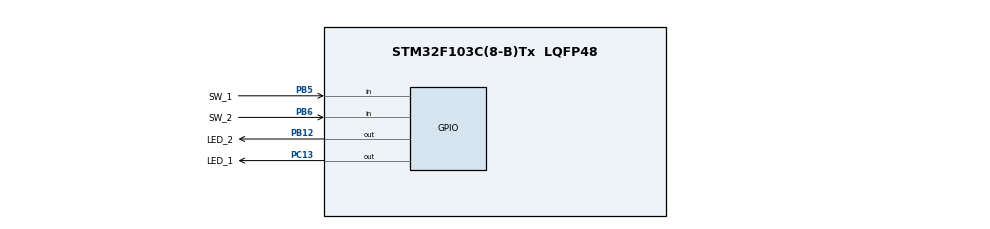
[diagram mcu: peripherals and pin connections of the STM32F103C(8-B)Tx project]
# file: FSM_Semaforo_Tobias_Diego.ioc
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Mcu.Family=STM32F1
Mcu.Name=STM32F103C(8-B)Tx
Mcu.Package=LQFP48
NVIC.PriorityGroup=NVIC_PRIORITYGROUP_4
PA13.Mode=Serial_Wire
PA13.Signal=SYS_JTMS-SWDIO
PA14.Mode=Serial_Wire
PA14.Signal=SYS_JTCK-SWCLK
PB12.GPIO_Label=LED_2
PB12.Signal=GPIO_Output
PB5.GPIO_Label=SW_1
PB5.GPIO_PuPd=GPIO_PULLDOWN
PB5.Signal=GPIO_Input
PB6.GPIO_Label=SW_2
PB6.GPIO_PuPd=GPIO_PULLDOWN
PB6.Signal=GPIO_Input
PC13-TAMPER-RTC.GPIO_Label=LED_1
PC13-TAMPER-RTC.Signal=GPIO_Output
PD0-OSC_IN.Mode=HSE-External-Clock-Source
PD0-OSC_IN.Signal=RCC_OSC_IN
PD1-OSC_OUT.Mode=HSE-External-Clock-Source
PD1-OSC_OUT.Signal=RCC_OSC_OUT
ProjectManager.HeapSize=0x200
ProjectManager.StackSize=0x400
ProjectManager.TargetToolchain=STM32CubeIDE
RCC.AHBFreq_Value=72000000
RCC.APB1CLKDivider=RCC_HCLK_DIV2
RCC.APB1Freq_Value=36000000
RCC.APB1TimFreq_Value=72000000
RCC.APB2Freq_Value=72000000
RCC.APB2TimFreq_Value=72000000
RCC.HCLKFreq_Value=72000000
RCC.PLLMUL=RCC_PLL_MUL9
RCC.PLLSourceVirtual=RCC_PLLSOURCE_HSE
RCC.SYSCLKFreq_VALUE=72000000
RCC.SYSCLKSource=RCC_SYSCLKSOURCE_PLLCLK
RCC.USBFreq_Value=72000000
board=custom

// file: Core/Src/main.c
/* USER CODE BEGIN Header */
/**
 ******************************************************************************
 * @file           : main.c
 * @brief          : Main program body
 ******************************************************************************
 * @attention
 *
 * Copyright (c) 2024 STMicroelectronics.
 * All rights reserved.
 *
 * This software is licensed under terms that can be found in the LICENSE file
 * in the root directory of this software component.
 * If no LICENSE file comes with this software, it is provided AS-IS.
 *
 ******************************************************************************
 */
/* USER CODE END Header */
#include "main.h"

/* USER CODE BEGIN Includes */
#include <string.h>
#include <stdio.h>

//#include "blink_control.h"
//#include "timer_period_manager.h"
#include "timer.h"
#include "modulo_ejemplo.h"
#include "blink_control.h"
/* USER CODE END Includes */

/* USER CODE BEGIN PV */
// Low-power mode aids
//Timer tick,sys_tick_2;
//unsigned int bandera=0;

//DebouncedSwitch debounced_button1, debounced_button2;
//EdgeDetector edge_detector1, edge_detector2;
//TimerPeriodManager period_manager1, period_manager2;

ModuloEjemplo proyecto1;

/* USER CODE END PV */

void SystemClock_Config(void);
static void MX_GPIO_Init(void);

int main(void)
{

	/* MCU Configuration--------------------------------------------------------*/

	/* Reset of all peripherals, Initializes the Flash interface and the Systick. */
	HAL_Init();

	/* Configure the system clock */
	SystemClock_Config();

	/* Initialize all configured peripherals */
	MX_GPIO_Init();
	/* USER CODE BEGIN 2 */
	//	debounced_switch_init(&debounced_button1, SW_1_GPIO_Port, SW_1_Pin);
	//	debounced_switch_init(&debounced_button2, SW_2_GPIO_Port, SW_2_Pin);
	//	edge_detector_init(&edge_detector1, &debounced_button1);
	//	edge_detector_init(&edge_detector2, &debounced_button2);
	//	timer_period_manager_init(&period_manager1, &blink_control_led1.blink_timer, &edge_detector1);
	//	timer_period_manager_init(&period_manager2, &blink_control_led1.blink_timer, &edge_detector2);
	modulo_ejemplo_init(&proyecto1, LED_1_GPIO_Port, LED_1_Pin, LED_2_GPIO_Port, LED_2_Pin, SW_1_GPIO_Port, SW_1_Pin, SW_2_GPIO_Port, SW_2_Pin);

	HAL_GPIO_WritePin(LED_1_GPIO_Port, LED_1_Pin, 1);
	HAL_GPIO_WritePin(LED_2_GPIO_Port, LED_2_Pin, 0);
	/* USER CODE END 2 */

	/* Infinite loop */
	/* USER CODE BEGIN WHILE */
	while (1)
	{

		modulo_ejemplo_update(&proyecto1);

		//		while(!timer_has_expired(&tick)) {
		//			HAL_PWR_EnterSLEEPMode(PWR_MAINREGULATOR_ON, PWR_SLEEPENTRY_WFI);
		//		}
		/* USER CODE END WHILE */

	}
}

void SystemClock_Config(void)
{
	RCC_OscInitTypeDef RCC_OscInitStruct = {0};
	RCC_ClkInitTypeDef RCC_ClkInitStruct = {0};

	/** Initializes the RCC Oscillators according to the specified parameters
	 * in the RCC_OscInitTypeDef structure.
	 */
	RCC_OscInitStruct.OscillatorType = RCC_OSCILLATORTYPE_HSI;
	RCC_OscInitStruct.HSIState = RCC_HSI_ON;
	RCC_OscInitStruct.HSICalibrationValue = RCC_HSICALIBRATION_DEFAULT;
	RCC_OscInitStruct.PLL.PLLState = RCC_PLL_NONE;
	if (HAL_RCC_OscConfig(&RCC_OscInitStruct) != HAL_OK)
	{
		Error_Handler();
	}

	/** Initializes the CPU, AHB and APB buses clocks
	 */
	RCC_ClkInitStruct.ClockType = RCC_CLOCKTYPE_HCLK|RCC_CLOCKTYPE_SYSCLK
			|RCC_CLOCKTYPE_PCLK1|RCC_CLOCKTYPE_PCLK2;
	RCC_ClkInitStruct.SYSCLKSource = RCC_SYSCLKSOURCE_HSI;
	RCC_ClkInitStruct.AHBCLKDivider = RCC_SYSCLK_DIV1;
	RCC_ClkInitStruct.APB1CLKDivider = RCC_HCLK_DIV1;
	RCC_ClkInitStruct.APB2CLKDivider = RCC_HCLK_DIV1;

	if (HAL_RCC_ClockConfig(&RCC_ClkInitStruct, FLASH_LATENCY_0) != HAL_OK)
	{
		Error_Handler();
	}
}

static void MX_GPIO_Init(void)
{
	GPIO_InitTypeDef GPIO_InitStruct = {0};

	/* GPIO Ports Clock Enable */
	__HAL_RCC_GPIOC_CLK_ENABLE();
	__HAL_RCC_GPIOB_CLK_ENABLE();
	__HAL_RCC_GPIOA_CLK_ENABLE();

	/*Configure GPIO pin Output Level */
	HAL_GPIO_WritePin(LED_1_GPIO_Port, LED_1_Pin, GPIO_PIN_RESET);

	/*Configure GPIO pin Output Level */
	HAL_GPIO_WritePin(LED_2_GPIO_Port, LED_2_Pin, GPIO_PIN_RESET);

	/*Configure GPIO pin : LED_1_Pin */
	GPIO_InitStruct.Pin = LED_1_Pin;
	GPIO_InitStruct.Mode = GPIO_MODE_OUTPUT_PP;
	GPIO_InitStruct.Pull = GPIO_NOPULL;
	GPIO_InitStruct.Speed = GPIO_SPEED_FREQ_LOW;
	HAL_GPIO_Init(LED_1_GPIO_Port, &GPIO_InitStruct);

	/*Configure GPIO pin : LED_2_Pin */
	GPIO_InitStruct.Pin = LED_2_Pin;
	GPIO_InitStruct.Mode = GPIO_MODE_OUTPUT_PP;
	GPIO_InitStruct.Pull = GPIO_NOPULL;
	GPIO_InitStruct.Speed = GPIO_SPEED_FREQ_LOW;
	HAL_GPIO_Init(LED_2_GPIO_Port, &GPIO_InitStruct);

	/*Configure GPIO pins : SW_1_Pin SW_2_Pin */
	GPIO_InitStruct.Pin = SW_1_Pin|SW_2_Pin;
	GPIO_InitStruct.Mode = GPIO_MODE_INPUT;
	GPIO_InitStruct.Pull = GPIO_PULLDOWN;
	HAL_GPIO_Init(GPIOB, &GPIO_InitStruct);

}

/* USER CODE BEGIN 4 */
/**
 * @brief  Retargets the C library printf function to the USART.
 *   None
 * @retval None
 */

/* USER CODE END 4 */

void Error_Handler(void)
{
	__disable_irq();
	while (1)
	{
	}
}
